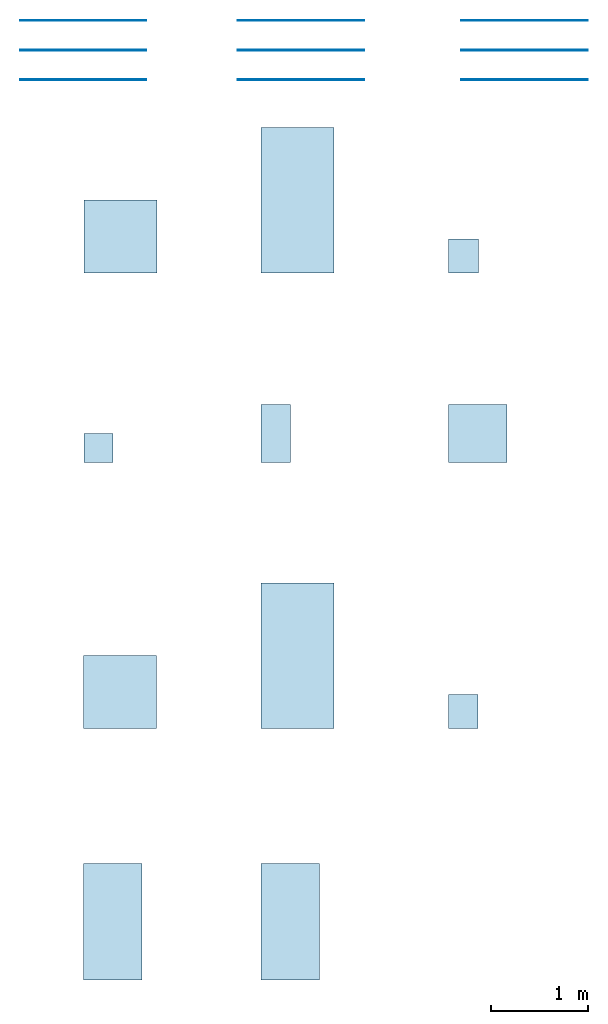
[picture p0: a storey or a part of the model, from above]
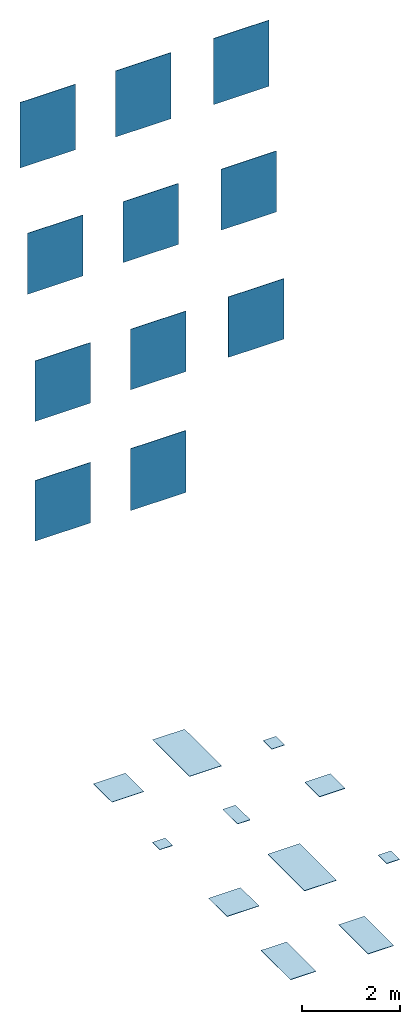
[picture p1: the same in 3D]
Properties of the parts of a building model (IFC2X3)

# File
Description: ViewDefinition [CoordinationView_V2.0], RevitIdentifiers [VersionGUID: 5640c061-cf9c-4f19-a32b-199643b3ba5e, NumberOfSaves: 302], CoordinateReference [CoordinateBase: Shared Coordinates, ProjectSite: Internal]
File name: Project Number
Time: 2025-02-25T16:56:37+01:00
Written by: ODA SDAI 24.3
Made in: Autodesk Revit 24.1.11.26 (ENU) - IFC 24.1.11.26

# IfcProject, Project Number
LongName: Refin-Blended; Phase: Project Status

# IfcSite, Default
RefLatitude: 51, 30, 0, 549316; RefLongitude: 0, -7, -34, -450321; RefElevation: 0 mm

# IfcBuilding
Pset_BuildingCommon - NumberOfStoreys: 1

# IfcBuildingStorey: Level:Circle Head - Project Datum (2)
Pset_AirSideSystemInformation - sets with these values: 2
Name | LongName = Name | Elevation (mm)
Level 0 | Level 0 | 0
Level 1 | Level 1 | 4000

# IfcSlab: Floor:Floor_Tiles_Refin-Prestigio_Travertino-Dorico-Grigio-60x120 RK80, Floor:Floor_Tiles_Refin-Prestigio_Travertino-Dorico-Grigio-60x120 RK80:350427
In: Level 0
Type - PredefinedType: FLOOR; Material: Prestigio Travertino-Dorico-Grigio-60x120 RK80 9 mm, <Unnamed> 1 mm
Type - Pset_ConcreteElementGeneral - FireRating: INERT
Type - Pset_ElementShading - Color: GREY
Type - Pset_FireRatingProperties - SurfaceSpreadOfFlame: INERT
Type - Pset_ManufacturerOccurrence - BarCode: N/A; SerialNumber: N/A
Type - Pset_ManufacturerTypeInformation - ArticleNumber: RK80; ModelReference: RK80; ModelLabel: GRIGIO SOFT 60X120; Manufacturer: info@refin.it; ProductionYear: N/A
Type - Pset_PrecastConcreteElementGeneral - SerialNumber: N/A
Type - Pset_ProductRequirements - Name: Prestigio_Travertino_Dorico_Grigio_60X120; Category: Pr_35_93_96_19:Ceramic tiles
Type - Pset_QuantityTakeOff - Reference: N/A
Type - Pset_ReinforcementBarPitchOfSlab - Description: PORCELAIN STONEWARE TILE; Reference: N/A
Type - Pset_SlabCommon - Reference: N/A; IsExternal: no; AcousticRating: N/A; FireRating: INERT; SurfaceSpreadOfFlame: INERT
Type - Pset_Warranty - WarrantyContent: N/A; Exclusions: N/A
Pset_QuantityTakeOff - sets with these values: 2
Pset_SlabCommon - LoadBearing: no; PitchAngle: 0 deg

# IfcSlab: Floor:Floor_Tiles_Refin-Prestigio_Travertino-Grigio-Lucido-75x75 OO03, Floor:Floor_Tiles_Refin-Prestigio_Travertino-Grigio-Lucido-75x75 OO03:304668
In: Level 0
Type - PredefinedType: FLOOR; Material: Prestigio Travertino-Grigio-Lucido-75x75 OO03 9 mm, <Unnamed> 1 mm
Type - Pset_ConcreteElementGeneral - FireRating: INERT
Type - Pset_ElementShading - Color: LIGHT GREY
Type - Pset_FireRatingProperties - SurfaceSpreadOfFlame: INERT
Type - Pset_ManufacturerOccurrence - BarCode: N/A; SerialNumber: N/A
Type - Pset_ManufacturerTypeInformation - ArticleNumber: OO03; ModelReference: OO03; ModelLabel: GRIGIO LUCIDO 75X75; Manufacturer: info@refin.it; ProductionYear: N/A
Type - Pset_PrecastConcreteElementGeneral - SerialNumber: N/A
Type - Pset_ProductRequirements - Name: Prestigio_Travertino_Grigio_Lucido_75X75; Category: Pr_35_93_96_19:Ceramic tiles
Type - Pset_QuantityTakeOff - Reference: N/A
Type - Pset_ReinforcementBarPitchOfSlab - Description: PORCELAIN STONEWARE TILE; Reference: N/A
Type - Pset_SlabCommon - Reference: N/A; IsExternal: no; AcousticRating: N/A; FireRating: INERT; SurfaceSpreadOfFlame: INERT
Type - Pset_Warranty - WarrantyContent: N/A; Exclusions: N/A
Pset_QuantityTakeOff - sets with these values: 2
Pset_SlabCommon - LoadBearing: no; PitchAngle: 0 deg

# IfcSlab: Floor:Floor_Tiles_Refin-Prestigio_Travertino-Grigio-Lucido-Mosaico-Cube 30.4x35.2 OO32, Floor:Floor_Tiles_Refin-Prestigio_Travertino-Grigio-Lucido-Mosaico-Cube 30.4x35.2 OO32:285295
In: Level 0
Type - PredefinedType: FLOOR; Material: Prestigio Travertino-Grigio-Lucido-Mosaico-Cube 30.4x35.2 OO32 9 mm, <Unnamed> 1 mm
Type - Pset_ConcreteElementGeneral - FireRating: INERT
Type - Pset_ElementShading - Color: LIGHT GREY
Type - Pset_FireRatingProperties - SurfaceSpreadOfFlame: INERT
Type - Pset_ManufacturerOccurrence - BarCode: N/A; SerialNumber: N/A
Type - Pset_ManufacturerTypeInformation - ArticleNumber: OO32; ModelReference: OO32; ModelLabel: GRIGIO LUCIDO MOSAICO CUBE 30.4X35.2; Manufacturer: info@refin.it; ProductionYear: N/A
Type - Pset_PrecastConcreteElementGeneral - SerialNumber: N/A
Type - Pset_ProductRequirements - Name: Prestigio_Travertino_Grigio_Lucido_Mosaico_Cube_30.4X35.2; Category: Pr_35_93_96_19:Ceramic tiles
Type - Pset_QuantityTakeOff - Reference: N/A
Type - Pset_ReinforcementBarPitchOfSlab - Description: PORCELAIN STONEWARE TILE; Reference: N/A
Type - Pset_SlabCommon - Reference: N/A; IsExternal: no; AcousticRating: N/A; FireRating: INERT; SurfaceSpreadOfFlame: INERT
Type - Pset_Warranty - WarrantyContent: N/A; Exclusions: N/A
Pset_QuantityTakeOff - sets with these values: 2
Pset_SlabCommon - LoadBearing: no; PitchAngle: 0 deg

# IfcSlab: Floor:Floor_Tiles_Refin-Prestigio_Travertino-Grigio-Lucido-Mosaico-T 30x30 OO38, Floor:Floor_Tiles_Refin-Prestigio_Travertino-Grigio-Lucido-Mosaico-T 30x30 OO38:304956
In: Level 0
Type - PredefinedType: FLOOR; Material: Prestigio Travertino-Grigio-Mix-Mosaico-T 30x30 OO38 9 mm, <Unnamed> 1 mm
Type - Pset_ConcreteElementGeneral - FireRating: INERT
Type - Pset_ElementShading - Color: LIGHT GREY
Type - Pset_FireRatingProperties - SurfaceSpreadOfFlame: INERT
Type - Pset_ManufacturerOccurrence - BarCode: N/A; SerialNumber: N/A
Type - Pset_ManufacturerTypeInformation - ArticleNumber: OO38; ModelReference: OO38; ModelLabel: GRIGIO MIX MOSAICO T 3X30; Manufacturer: info@refin.it; ProductionYear: N/A
Type - Pset_PrecastConcreteElementGeneral - SerialNumber: N/A
Type - Pset_ProductRequirements - Name: Prestigio_Travertino_Grigio_Mix_Mosaico_T_3X30; Category: Pr_35_93_96_19:Ceramic tiles
Type - Pset_QuantityTakeOff - Reference: N/A
Type - Pset_ReinforcementBarPitchOfSlab - Description: PORCELAIN STONEWARE TILE; Reference: N/A
Type - Pset_SlabCommon - Reference: N/A; IsExternal: no; AcousticRating: N/A; FireRating: INERT; SurfaceSpreadOfFlame: INERT
Type - Pset_Warranty - WarrantyContent: N/A; Exclusions: N/A
Pset_QuantityTakeOff - sets with these values: 2
Pset_SlabCommon - LoadBearing: no; PitchAngle: 0 deg

# IfcSlab: Floor:Floor_Tiles_Refin-Prestigio_Travertino-Grigio-Soft-30x60 OO09, Floor:Floor_Tiles_Refin-Prestigio_Travertino-Grigio-Soft-30x60 OO09:304948
In: Level 0
Type - PredefinedType: FLOOR; Material: Prestigio Travertino-Grigio-Soft-30x60 OO09 9 mm, <Unnamed> 1 mm
Type - Pset_ConcreteElementGeneral - FireRating: INERT
Type - Pset_ElementShading - Color: LIGHT GREY
Type - Pset_FireRatingProperties - SurfaceSpreadOfFlame: INERT
Type - Pset_ManufacturerOccurrence - BarCode: N/A; SerialNumber: N/A
Type - Pset_ManufacturerTypeInformation - ArticleNumber: OO09; ModelReference: OO09; ModelLabel: GRIGIO SOFT 30X60; Manufacturer: info@refin.it; ProductionYear: N/A
Type - Pset_PrecastConcreteElementGeneral - SerialNumber: N/A
Type - Pset_ProductRequirements - Name: Prestigio_Travertino_Grigio_Soft_30X60; Category: Pr_35_93_96_19:Ceramic tiles
Type - Pset_QuantityTakeOff - Reference: N/A
Type - Pset_ReinforcementBarPitchOfSlab - Description: PORCELAIN STONEWARE TILE; Reference: N/A
Type - Pset_SlabCommon - Reference: N/A; IsExternal: no; AcousticRating: N/A; FireRating: INERT; SurfaceSpreadOfFlame: INERT
Type - Pset_Warranty - WarrantyContent: N/A; Exclusions: N/A
Pset_QuantityTakeOff - sets with these values: 2
Pset_SlabCommon - LoadBearing: no; PitchAngle: 0 deg

# IfcSlab: Floor:Floor_Tiles_Refin-Prestigio_Travertino-Grigio-Soft-60x120 OZ37, Floor:Floor_Tiles_Refin-Prestigio_Travertino-Grigio-Soft-60x120 OZ37:349976
In: Level 0
Type - PredefinedType: FLOOR; Material: Prestigio Travertino-Grigio-Soft-60x120 OZ37 9 mm, <Unnamed> 1 mm
Type - Pset_ConcreteElementGeneral - FireRating: INERT
Type - Pset_ElementShading - Color: GREY
Type - Pset_FireRatingProperties - SurfaceSpreadOfFlame: INERT
Type - Pset_ManufacturerOccurrence - BarCode: N/A; SerialNumber: N/A
Type - Pset_ManufacturerTypeInformation - ArticleNumber: OZ37; ModelReference: OZ37; ModelLabel: GRIGIO SOFT 60X120; Manufacturer: info@refin.it; ProductionYear: N/A
Type - Pset_PrecastConcreteElementGeneral - SerialNumber: N/A
Type - Pset_ProductRequirements - Name: Prestigio_Travertino_Grigio_Soft_60X120; Category: Pr_35_93_96_19:Ceramic tiles
Type - Pset_QuantityTakeOff - Reference: N/A
Type - Pset_ReinforcementBarPitchOfSlab - Description: PORCELAIN STONEWARE TILE; Reference: N/A
Type - Pset_SlabCommon - Reference: N/A; IsExternal: no; AcousticRating: N/A; FireRating: INERT; SurfaceSpreadOfFlame: INERT
Type - Pset_Warranty - WarrantyContent: N/A; Exclusions: N/A
Pset_QuantityTakeOff - sets with these values: 2
Pset_SlabCommon - LoadBearing: no; PitchAngle: 0 deg

# IfcSlab: Floor:Floor_Tiles_Refin-Prestigio_Travertino-Grigio-Soft-60x60 OO06, Floor:Floor_Tiles_Refin-Prestigio_Travertino-Grigio-Soft-60x60 OO06:304932
In: Level 0
Type - PredefinedType: FLOOR; Material: Prestigio Travertino-Grigio-Soft-60x60 OO06 9 mm, <Unnamed> 1 mm
Type - Pset_ConcreteElementGeneral - FireRating: INERT
Type - Pset_ElementShading - Color: LIGHT GREY
Type - Pset_FireRatingProperties - SurfaceSpreadOfFlame: INERT
Type - Pset_ManufacturerOccurrence - BarCode: N/A; SerialNumber: N/A
Type - Pset_ManufacturerTypeInformation - ArticleNumber: OO06; ModelReference: OO06; ModelLabel: GRIGIO SOFT 60X60; Manufacturer: info@refin.it; ProductionYear: N/A
Type - Pset_PrecastConcreteElementGeneral - SerialNumber: N/A
Type - Pset_ProductRequirements - Name: Prestigio_Travertino_Grigio_Soft_60X60; Category: Pr_35_93_96_19:Ceramic tiles
Type - Pset_QuantityTakeOff - Reference: N/A
Type - Pset_ReinforcementBarPitchOfSlab - Description: PORCELAIN STONEWARE TILE; Reference: N/A
Type - Pset_SlabCommon - Reference: N/A; IsExternal: no; AcousticRating: N/A; FireRating: INERT; SurfaceSpreadOfFlame: INERT
Type - Pset_Warranty - WarrantyContent: N/A; Exclusions: N/A
Pset_QuantityTakeOff - sets with these values: 2
Pset_SlabCommon - LoadBearing: no; PitchAngle: 0 deg

# IfcSlab: Floor:Floor_Tiles_Refin-Prestigio_Travertino-Grigio-Soft-75x150 OM85, Floor:Floor_Tiles_Refin-Prestigio_Travertino-Grigio-Soft-75x150 OM85:339635
In: Level 0
Type - PredefinedType: FLOOR; Material: Prestigio Travertino-Grigio-Soft-75x150 OM85 9 mm, <Unnamed> 1 mm
Type - Pset_ConcreteElementGeneral - FireRating: INERT
Type - Pset_ElementShading - Color: LIGHT GREY
Type - Pset_FireRatingProperties - SurfaceSpreadOfFlame: INERT
Type - Pset_ManufacturerOccurrence - BarCode: N/A; SerialNumber: N/A
Type - Pset_ManufacturerTypeInformation - ArticleNumber: OM85; ModelReference: OM85; ModelLabel: GRIGIO SOFT 75X150; Manufacturer: info@refin.it; ProductionYear: N/A
Type - Pset_PrecastConcreteElementGeneral - SerialNumber: N/A
Type - Pset_ProductRequirements - Name: Prestigio_Travertino_Grigio_Soft_75X150; Category: Pr_35_93_96_19:Ceramic tiles
Type - Pset_QuantityTakeOff - Reference: N/A
Type - Pset_ReinforcementBarPitchOfSlab - Description: PORCELAIN STONEWARE TILE; Reference: N/A
Type - Pset_SlabCommon - Reference: N/A; IsExternal: no; AcousticRating: N/A; FireRating: INERT; SurfaceSpreadOfFlame: INERT
Type - Pset_Warranty - WarrantyContent: N/A; Exclusions: N/A
Pset_QuantityTakeOff - sets with these values: 2
Pset_SlabCommon - LoadBearing: no; PitchAngle: 0 deg

# IfcSlab: Floor:Floor_Tiles_Refin-Prestigio_Travertino-Grigio-Soft-75x150 OM88, Floor:Floor_Tiles_Refin-Prestigio_Travertino-Grigio-Soft-75x150 OM88:324498
In: Level 0
Type - PredefinedType: FLOOR; Material: Prestigio Travertino-Grigio-Lucido-75x150 OM88 9 mm, <Unnamed> 1 mm
Type - Pset_ConcreteElementGeneral - FireRating: INERT
Type - Pset_ElementShading - Color: LIGHT GREY
Type - Pset_FireRatingProperties - SurfaceSpreadOfFlame: INERT
Type - Pset_ManufacturerOccurrence - BarCode: N/A; SerialNumber: N/A
Type - Pset_ManufacturerTypeInformation - ArticleNumber: OM88; ModelReference: OM88; ModelLabel: GRIGIO LUCIDO 75X150; Manufacturer: info@refin.it; ProductionYear: N/A
Type - Pset_PrecastConcreteElementGeneral - SerialNumber: N/A
Type - Pset_ProductRequirements - Name: Prestigio_Travertino_Grigio_Lucido_75X150; Category: Pr_35_93_96_19:Ceramic tiles
Type - Pset_QuantityTakeOff - Reference: N/A
Type - Pset_ReinforcementBarPitchOfSlab - Description: PORCELAIN STONEWARE TILE; Reference: N/A
Type - Pset_SlabCommon - Reference: N/A; IsExternal: no; AcousticRating: N/A; FireRating: INERT; SurfaceSpreadOfFlame: INERT
Type - Pset_Warranty - WarrantyContent: N/A; Exclusions: N/A
Pset_QuantityTakeOff - sets with these values: 2
Pset_SlabCommon - LoadBearing: no; PitchAngle: 0 deg

# IfcSlab: Floor:Floor_Tiles_Refin-Prestigio_Travertino-Grigio-Soft-75x75 OO00, Floor:Floor_Tiles_Refin-Prestigio_Travertino-Grigio-Soft-75x75 OO00:305509
In: Level 0
Type - PredefinedType: FLOOR; Material: Prestigio Travertino-Grigio-Soft-75x75 OO00 9 mm, <Unnamed> 1 mm
Type - Pset_ConcreteElementGeneral - FireRating: INERT
Type - Pset_ElementShading - Color: LIGHT GREY
Type - Pset_FireRatingProperties - SurfaceSpreadOfFlame: INERT
Type - Pset_ManufacturerOccurrence - BarCode: N/A; SerialNumber: N/A
Type - Pset_ManufacturerTypeInformation - ArticleNumber: OO00; ModelReference: OO00; ModelLabel: GRIGIO SOFT 75X75; Manufacturer: info@refin.it; ProductionYear: N/A
Type - Pset_PrecastConcreteElementGeneral - SerialNumber: N/A
Type - Pset_ProductRequirements - Name: Prestigio_Travertino_Grigio_Soft_75X75; Category: Pr_35_93_96_19:Ceramic tiles
Type - Pset_QuantityTakeOff - Reference: N/A
Type - Pset_ReinforcementBarPitchOfSlab - Description: PORCELAIN STONEWARE TILE; Reference: N/A
Type - Pset_SlabCommon - Reference: N/A; IsExternal: no; AcousticRating: N/A; FireRating: INERT; SurfaceSpreadOfFlame: INERT
Type - Pset_Warranty - WarrantyContent: N/A; Exclusions: N/A
Pset_QuantityTakeOff - sets with these values: 2
Pset_SlabCommon - LoadBearing: no; PitchAngle: 0 deg

# IfcSlab: Floor:Floor_Tiles_Refin-Prestigio_Travertino-Grigio-Soft-Mosaico-Cube 30.4x35.2 OO35, Floor:Floor_Tiles_Refin-Prestigio_Travertino-Grigio-Soft-Mosaico-Cube 30.4x35.2 OO35:339650
In: Level 0
Type - PredefinedType: FLOOR; Material: Prestigio Travertino-Grigio-Soft-Mosaico-Cube 30.4x35.2 OO35 9 mm, <Unnamed> 1 mm
Type - Pset_ConcreteElementGeneral - FireRating: INERT
Type - Pset_ElementShading - Color: LIGHT GREY
Type - Pset_FireRatingProperties - SurfaceSpreadOfFlame: INERT
Type - Pset_ManufacturerOccurrence - BarCode: N/A; SerialNumber: N/A
Type - Pset_ManufacturerTypeInformation - ArticleNumber: OO35; ModelReference: OO35; ModelLabel: GRIGIO SOFT MOSAICO CUBE 30.4X35.2; Manufacturer: info@refin.it; ProductionYear: N/A
Type - Pset_PrecastConcreteElementGeneral - SerialNumber: N/A
Type - Pset_ProductRequirements - Name: Prestigio_Travertino_Grigio_Soft_Mosaico_Cube_30.4X35.2; Category: Pr_35_93_96_19:Ceramic tiles
Type - Pset_QuantityTakeOff - Reference: N/A
Type - Pset_ReinforcementBarPitchOfSlab - Description: PORCELAIN STONEWARE TILE; Reference: N/A
Type - Pset_SlabCommon - Reference: N/A; IsExternal: no; AcousticRating: N/A; FireRating: INERT; SurfaceSpreadOfFlame: INERT
Type - Pset_Warranty - WarrantyContent: N/A; Exclusions: N/A
Pset_QuantityTakeOff - sets with these values: 2
Pset_SlabCommon - LoadBearing: no; PitchAngle: 0 deg

# IfcWallStandardCase: Basic Wall:Floor_Tiles_Refin-Prestigio_Travertino-Dorico-Grigio-60x120 RK80, Basic Wall:Floor_Tiles_Refin-Prestigio_Travertino-Dorico-Grigio-60x120 RK80:350469
In: Level 0
Type - PredefinedType: STANDARD; Material: <Unnamed> 1 mm, Prestigio Travertino-Dorico-Grigio-60x120 RK80 9 mm
Type - Pset_ElementShading - Color: GREY
Type - Pset_FireRatingProperties - SurfaceSpreadOfFlame: INERT
Type - Pset_ManufacturerOccurrence - BarCode: N/A; SerialNumber: N/A
Type - Pset_ManufacturerTypeInformation - ArticleNumber: RK80; ModelReference: RK80; ModelLabel: DORICO GRIGIO 60X120; Manufacturer: info@refin.it; ProductionYear: N/A
Type - Pset_PrecastConcreteElementGeneral - SerialNumber: N/A
Type - Pset_ProductRequirements - Name: Prestigio Travertino_Dorico_Grigio_60X120; Category: Pr_35_93_96_19:Ceramic tiles
Type - Pset_QuantityTakeOff - Reference: N/A
Type - Pset_ReinforcementBarPitchOfWall - Description: PORCELAIN STONEWARE TILE; Reference: N/A
Type - Pset_WallCommon - Reference: N/A; IsExternal: no; AcousticRating: N/A; SurfaceSpreadOfFlame: INERT
Type - Pset_Warranty - WarrantyContent: N/A; Exclusions: N/A
Pset_QuantityTakeOff - sets with these values: 2
Pset_WallCommon - LoadBearing: no; ExtendToStructure: no

# IfcWallStandardCase: Basic Wall:Floor_Tiles_Refin-Prestigio_Travertino-Grigio-Lucido-75x150 OM88, Basic Wall:Floor_Tiles_Refin-Prestigio_Travertino-Grigio-Lucido-75x150 OM88:333696
In: Level 0
Type - PredefinedType: STANDARD; Material: <Unnamed> 1 mm, Prestigio Travertino-Grigio-Lucido-75x150 OM88 9 mm
Type - Pset_ElementShading - Color: LIGHT GREY
Type - Pset_FireRatingProperties - SurfaceSpreadOfFlame: INERT
Type - Pset_ManufacturerOccurrence - BarCode: N/A; SerialNumber: N/A
Type - Pset_ManufacturerTypeInformation - ArticleNumber: OM88; ModelReference: OM88; ModelLabel: GRIGIO LUCIDO 75X150; Manufacturer: info@refin.it; ProductionYear: N/A
Type - Pset_PrecastConcreteElementGeneral - SerialNumber: N/A
Type - Pset_ProductRequirements - Name: Prestigio Travertino_Grigio_Lucido_75X150; Category: Pr_35_93_96_19:Ceramic tiles
Type - Pset_QuantityTakeOff - Reference: N/A
Type - Pset_ReinforcementBarPitchOfWall - Description: PORCELAIN STONEWARE TILE; Reference: N/A
Type - Pset_WallCommon - Reference: N/A; IsExternal: no; AcousticRating: N/A; SurfaceSpreadOfFlame: INERT
Type - Pset_Warranty - WarrantyContent: N/A; Exclusions: N/A
Pset_QuantityTakeOff - sets with these values: 2
Pset_WallCommon - LoadBearing: no; ExtendToStructure: no

# IfcWallStandardCase: Basic Wall:Floor_Tiles_Refin-Prestigio_Travertino-Grigio-Lucido-75x75 OO03, Basic Wall:Floor_Tiles_Refin-Prestigio_Travertino-Grigio-Lucido-75x75 OO03:334895
In: Level 0
Type - PredefinedType: STANDARD; Material: <Unnamed> 1 mm, Prestigio Travertino-Grigio-Lucido-75x75 OO03 9 mm
Type - Pset_ElementShading - Color: LIGHT GREY
Type - Pset_FireRatingProperties - SurfaceSpreadOfFlame: INERT
Type - Pset_ManufacturerOccurrence - BarCode: N/A; SerialNumber: N/A
Type - Pset_ManufacturerTypeInformation - ArticleNumber: OO03; ModelReference: OO03; ModelLabel: GRIGIO LUCIDO 75X75; Manufacturer: info@refin.it; ProductionYear: N/A
Type - Pset_PrecastConcreteElementGeneral - SerialNumber: N/A
Type - Pset_ProductRequirements - Name: Prestigio Travertino_Grigio_Lucido_75X75; Category: Pr_35_93_96_19:Ceramic tiles
Type - Pset_QuantityTakeOff - Reference: N/A
Type - Pset_ReinforcementBarPitchOfWall - Description: PORCELAIN STONEWARE TILE; Reference: N/A
Type - Pset_WallCommon - Reference: N/A; IsExternal: no; AcousticRating: N/A; SurfaceSpreadOfFlame: INERT
Type - Pset_Warranty - WarrantyContent: N/A; Exclusions: N/A
Pset_QuantityTakeOff - sets with these values: 2
Pset_WallCommon - LoadBearing: no; ExtendToStructure: no

# IfcWallStandardCase: Basic Wall:Floor_Tiles_Refin-Prestigio_Travertino-Grigio-Lucido-Mosaico-Cube 30.4x35.2 OO32, Basic Wall:Floor_Tiles_Refin-Prestigio_Travertino-Grigio-Lucido-Mosaico-Cube 30.4x35.2 OO32:334553
In: Level 0
Type - PredefinedType: STANDARD; Material: <Unnamed> 1 mm, Prestigio Travertino-Grigio-Lucido-Mosaico-Cube 30.4x35.2 OO32 9 mm
Type - Pset_ElementShading - Color: LIGHT GREY
Type - Pset_FireRatingProperties - SurfaceSpreadOfFlame: INERT
Type - Pset_ManufacturerOccurrence - BarCode: N/A; SerialNumber: N/A
Type - Pset_ManufacturerTypeInformation - ArticleNumber: OO32; ModelReference: OO32; ModelLabel: GRIGIO LUCIDO MOSAICO CUBE 30.4X35.2; Manufacturer: info@refin.it; ProductionYear: N/A
Type - Pset_PrecastConcreteElementGeneral - SerialNumber: N/A
Type - Pset_ProductRequirements - Name: Prestigio Travertino_Grigio_Lucido_Mosaico_Cube_30.4X35.2; Category: Pr_35_93_96_19:Ceramic tiles
Type - Pset_QuantityTakeOff - Reference: N/A
Type - Pset_ReinforcementBarPitchOfWall - Description: PORCELAIN STONEWARE TILE; Reference: N/A
Type - Pset_WallCommon - Reference: N/A; IsExternal: no; AcousticRating: N/A; SurfaceSpreadOfFlame: INERT
Type - Pset_Warranty - WarrantyContent: N/A; Exclusions: N/A
Pset_QuantityTakeOff - sets with these values: 2
Pset_WallCommon - LoadBearing: no; ExtendToStructure: no

# IfcWallStandardCase: Basic Wall:Floor_Tiles_Refin-Prestigio_Travertino-Grigio-Lucido-Mosaico-T 30x30 OO38, Basic Wall:Floor_Tiles_Refin-Prestigio_Travertino-Grigio-Lucido-Mosaico-T 30x30 OO38:335038
In: Level 0
Type - PredefinedType: STANDARD; Material: <Unnamed> 1 mm, Prestigio Travertino-Grigio-Mix-Mosaico-T 30x30 OO38 9 mm
Type - Pset_ElementShading - Color: LIGHT GREY
Type - Pset_FireRatingProperties - SurfaceSpreadOfFlame: INERT
Type - Pset_ManufacturerOccurrence - BarCode: N/A; SerialNumber: N/A
Type - Pset_ManufacturerTypeInformation - ArticleNumber: OO38; ModelReference: OO38; ModelLabel: GRIGIO MIX MOSAICO T 30X30; Manufacturer: info@refin.it; ProductionYear: N/A
Type - Pset_PrecastConcreteElementGeneral - SerialNumber: N/A
Type - Pset_ProductRequirements - Name: Prestigio Travertino_Grigio_Mix_Mosaico_T_30X30; Category: Pr_35_93_96_19:Ceramic tiles
Type - Pset_QuantityTakeOff - Reference: N/A
Type - Pset_ReinforcementBarPitchOfWall - Description: PORCELAIN STONEWARE TILE; Reference: N/A
Type - Pset_WallCommon - Reference: N/A; IsExternal: no; AcousticRating: N/A; SurfaceSpreadOfFlame: INERT
Type - Pset_Warranty - WarrantyContent: N/A; Exclusions: N/A
Pset_QuantityTakeOff - sets with these values: 2
Pset_WallCommon - LoadBearing: no; ExtendToStructure: no

# IfcWallStandardCase: Basic Wall:Floor_Tiles_Refin-Prestigio_Travertino-Grigio-Soft-30x60 OO09, Basic Wall:Floor_Tiles_Refin-Prestigio_Travertino-Grigio-Soft-30x60 OO09:335490
In: Level 0
Type - PredefinedType: STANDARD; Material: <Unnamed> 1 mm, Prestigio Travertino-Grigio-Soft-30x60 OO09 9 mm
Type - Pset_ElementShading - Color: LIGHT GREY
Type - Pset_FireRatingProperties - SurfaceSpreadOfFlame: INERT
Type - Pset_ManufacturerOccurrence - BarCode: N/A; SerialNumber: N/A
Type - Pset_ManufacturerTypeInformation - ArticleNumber: OO09; ModelReference: OO09; ModelLabel: GRIGIO SOFT 30X60; Manufacturer: info@refin.it; ProductionYear: N/A
Type - Pset_PrecastConcreteElementGeneral - SerialNumber: N/A
Type - Pset_ProductRequirements - Name: Prestigio Travertino_Grigio_Soft_30X60; Category: Pr_35_93_96_19:Ceramic tiles
Type - Pset_QuantityTakeOff - Reference: N/A
Type - Pset_ReinforcementBarPitchOfWall - Description: PORCELAIN STONEWARE TILE; Reference: N/A
Type - Pset_WallCommon - Reference: N/A; IsExternal: no; AcousticRating: N/A; SurfaceSpreadOfFlame: INERT
Type - Pset_Warranty - WarrantyContent: N/A; Exclusions: N/A
Pset_QuantityTakeOff - sets with these values: 2
Pset_WallCommon - LoadBearing: no; ExtendToStructure: no

# IfcWallStandardCase: Basic Wall:Floor_Tiles_Refin-Prestigio_Travertino-Grigio-Soft-60x120 OZ37, Basic Wall:Floor_Tiles_Refin-Prestigio_Travertino-Grigio-Soft-60x120 OZ37:350022
In: Level 0
Type - PredefinedType: STANDARD; Material: <Unnamed> 1 mm, Prestigio Travertino-Grigio-Soft-60x120 OZ37 9 mm
Type - Pset_ElementShading - Color: GREY
Type - Pset_FireRatingProperties - SurfaceSpreadOfFlame: INERT
Type - Pset_ManufacturerOccurrence - BarCode: N/A; SerialNumber: N/A
Type - Pset_ManufacturerTypeInformation - ArticleNumber: OZ37; ModelReference: OZ37; ModelLabel: GRIGIO SOFT 60X120; Manufacturer: info@refin.it; ProductionYear: N/A
Type - Pset_PrecastConcreteElementGeneral - SerialNumber: N/A
Type - Pset_ProductRequirements - Name: Prestigio Travertino_Grigio_Soft_60X120; Category: Pr_35_93_96_19:Ceramic tiles
Type - Pset_QuantityTakeOff - Reference: N/A
Type - Pset_ReinforcementBarPitchOfWall - Description: PORCELAIN STONEWARE TILE; Reference: N/A
Type - Pset_WallCommon - Reference: N/A; IsExternal: no; AcousticRating: N/A; SurfaceSpreadOfFlame: INERT
Type - Pset_Warranty - WarrantyContent: N/A; Exclusions: N/A
Pset_QuantityTakeOff - sets with these values: 2
Pset_WallCommon - LoadBearing: no; ExtendToStructure: no

# IfcWallStandardCase: Basic Wall:Floor_Tiles_Refin-Prestigio_Travertino-Grigio-Soft-60x60 OO06, Basic Wall:Floor_Tiles_Refin-Prestigio_Travertino-Grigio-Soft-60x60 OO06:335882
In: Level 0
Type - PredefinedType: STANDARD; Material: <Unnamed> 1 mm, Prestigio Travertino-Grigio-Soft-60x60 OO06 9 mm
Type - Pset_ElementShading - Color: LIGHT GREY
Type - Pset_FireRatingProperties - SurfaceSpreadOfFlame: INERT
Type - Pset_ManufacturerOccurrence - BarCode: N/A; SerialNumber: N/A
Type - Pset_ManufacturerTypeInformation - ArticleNumber: OO06; ModelReference: OO06; ModelLabel: GRIGIO SOFT 60X60; Manufacturer: info@refin.it; ProductionYear: N/A
Type - Pset_PrecastConcreteElementGeneral - SerialNumber: N/A
Type - Pset_ProductRequirements - Name: Prestigio Travertino_Grigio_Soft_60X60; Category: Pr_35_93_96_19:Ceramic tiles
Type - Pset_QuantityTakeOff - Reference: N/A
Type - Pset_ReinforcementBarPitchOfWall - Description: PORCELAIN STONEWARE TILE; Reference: N/A
Type - Pset_WallCommon - Reference: N/A; IsExternal: no; AcousticRating: N/A; SurfaceSpreadOfFlame: INERT
Type - Pset_Warranty - WarrantyContent: N/A; Exclusions: N/A
Pset_QuantityTakeOff - sets with these values: 2
Pset_WallCommon - LoadBearing: no; ExtendToStructure: no

# IfcWallStandardCase: Basic Wall:Floor_Tiles_Refin-Prestigio_Travertino-Grigio-Soft-75x150 OM85, Basic Wall:Floor_Tiles_Refin-Prestigio_Travertino-Grigio-Soft-75x150 OM85:339715
In: Level 0
Type - PredefinedType: STANDARD; Material: <Unnamed> 1 mm, Prestigio Travertino-Grigio-Soft-75x150 OM85 9 mm
Type - Pset_ElementShading - Color: LIGHT GREY
Type - Pset_FireRatingProperties - SurfaceSpreadOfFlame: INERT
Type - Pset_ManufacturerOccurrence - BarCode: N/A; SerialNumber: N/A
Type - Pset_ManufacturerTypeInformation - ArticleNumber: OM85; ModelReference: OM85; ModelLabel: GRIGIO SOFT 75X150; Manufacturer: info@refin.it; ProductionYear: N/A
Type - Pset_PrecastConcreteElementGeneral - SerialNumber: N/A
Type - Pset_ProductRequirements - Name: Prestigio Travertino_Grigio_Soft_75X150; Category: Pr_35_93_96_19:Ceramic tiles
Type - Pset_QuantityTakeOff - Reference: N/A
Type - Pset_ReinforcementBarPitchOfWall - Description: PORCELAIN STONEWARE TILE; Reference: N/A
Type - Pset_WallCommon - Reference: N/A; IsExternal: no; AcousticRating: N/A; SurfaceSpreadOfFlame: INERT
Type - Pset_Warranty - WarrantyContent: N/A; Exclusions: N/A
Pset_QuantityTakeOff - sets with these values: 2
Pset_WallCommon - LoadBearing: no; ExtendToStructure: no

# IfcWallStandardCase: Basic Wall:Floor_Tiles_Refin-Prestigio_Travertino-Grigio-Soft-75x75 OO00, Basic Wall:Floor_Tiles_Refin-Prestigio_Travertino-Grigio-Soft-75x75 OO00:336183
In: Level 0
Type - PredefinedType: STANDARD; Material: <Unnamed> 1 mm, Prestigio Travertino-Grigio-Soft-75x75 OO00 9 mm
Type - Pset_ElementShading - Color: LIGHT GREY
Type - Pset_FireRatingProperties - SurfaceSpreadOfFlame: INERT
Type - Pset_ManufacturerOccurrence - BarCode: N/A; SerialNumber: N/A
Type - Pset_ManufacturerTypeInformation - ArticleNumber: OO00; ModelReference: OO00; ModelLabel: GRIGIO SOFT 75X75; Manufacturer: info@refin.it; ProductionYear: N/A
Type - Pset_PrecastConcreteElementGeneral - SerialNumber: N/A
Type - Pset_ProductRequirements - Name: Prestigio_Travertino_Grigio_Soft_75X75; Category: Pr_35_93_96_19:Ceramic tiles
Type - Pset_QuantityTakeOff - Reference: N/A
Type - Pset_ReinforcementBarPitchOfWall - Description: PORCELAIN STONEWARE TILE; Reference: N/A
Type - Pset_WallCommon - Reference: N/A; IsExternal: no; AcousticRating: N/A; SurfaceSpreadOfFlame: INERT
Type - Pset_Warranty - WarrantyContent: N/A; Exclusions: N/A
Pset_QuantityTakeOff - sets with these values: 2
Pset_WallCommon - LoadBearing: no; ExtendToStructure: no

# IfcWallStandardCase: Basic Wall:Floor_Tiles_Refin-Prestigio_Travertino-Grigio-Soft-Mosaico-Cube 30.4x35.2 OO35, Basic Wall:Floor_Tiles_Refin-Prestigio_Travertino-Grigio-Soft-Mosaico-Cube 30.4x35.2 OO35:339723
In: Level 0
Type - PredefinedType: STANDARD; Material: <Unnamed> 1 mm, Prestigio Travertino-Grigio-Soft-Mosaico-Cube 30.4x35.2 OO35 9 mm
Type - Pset_ElementShading - Color: LIGHT GREY
Type - Pset_FireRatingProperties - SurfaceSpreadOfFlame: INERT
Type - Pset_ManufacturerOccurrence - BarCode: N/A; SerialNumber: N/A
Type - Pset_ManufacturerTypeInformation - ArticleNumber: OO35; ModelReference: OO35; ModelLabel: GRIGIO SOFT MOSAICO CUBE 30.4X35.2; Manufacturer: info@refin.it; ProductionYear: N/A
Type - Pset_PrecastConcreteElementGeneral - SerialNumber: N/A
Type - Pset_ProductRequirements - Name: Prestigio_Travertino_Grigio_Soft_Mosaico_Cube_30.4X35.2; Category: Pr_35_93_96_19:Ceramic tiles
Type - Pset_QuantityTakeOff - Reference: N/A
Type - Pset_ReinforcementBarPitchOfWall - Description: PORCELAIN STONEWARE TILE; Reference: N/A
Type - Pset_WallCommon - Reference: N/A; IsExternal: no; AcousticRating: N/A; SurfaceSpreadOfFlame: INERT
Type - Pset_Warranty - WarrantyContent: N/A; Exclusions: N/A
Pset_QuantityTakeOff - sets with these values: 2
Pset_WallCommon - LoadBearing: no; ExtendToStructure: no
